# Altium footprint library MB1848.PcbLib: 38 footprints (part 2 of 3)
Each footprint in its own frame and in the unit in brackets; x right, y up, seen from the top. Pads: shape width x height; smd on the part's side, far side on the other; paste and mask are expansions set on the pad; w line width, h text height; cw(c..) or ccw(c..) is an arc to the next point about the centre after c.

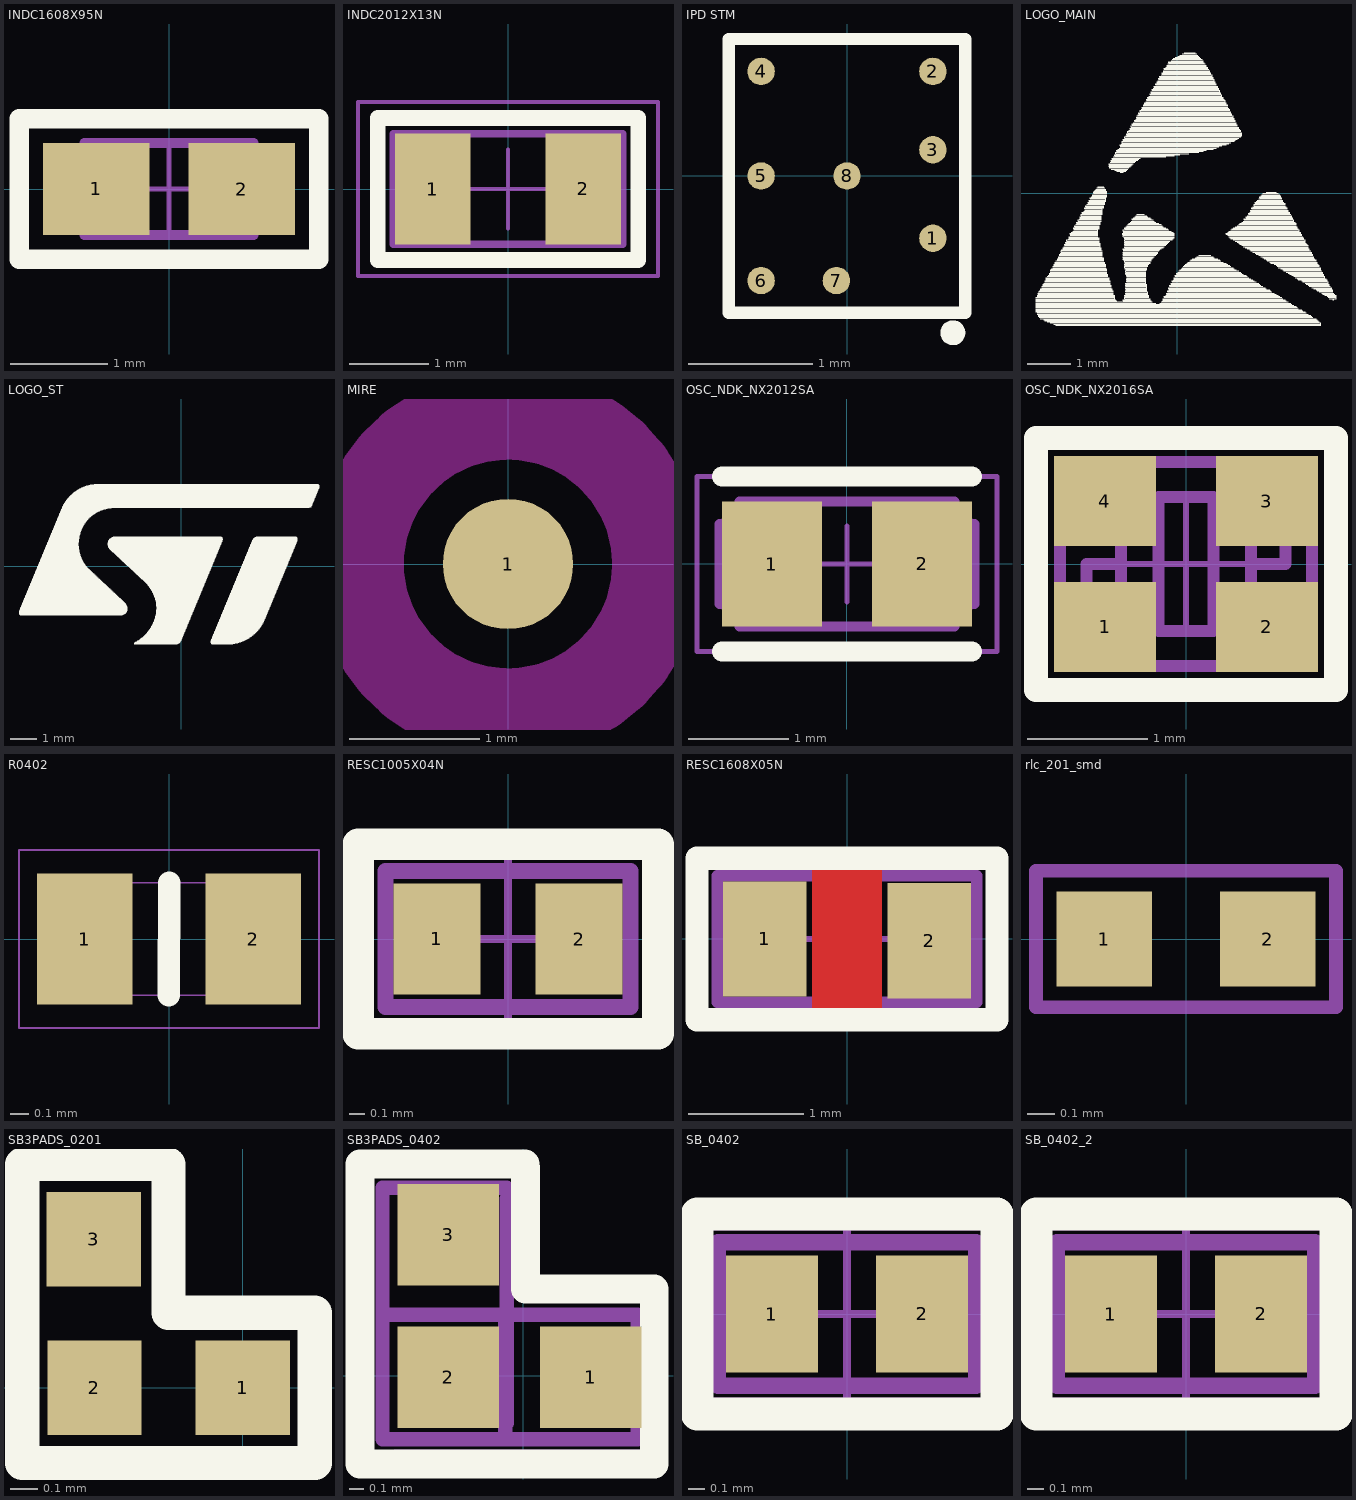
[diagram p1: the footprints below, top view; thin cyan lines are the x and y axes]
## INDC1608X95N [mm] "Chip Inductor, 2-Leads, Body 1.75x0.95x0.95mm (0603)"
height 0.95
pads (2):
  rect 1.1x0.95 smd: 1(-0.75,0) 2(0.75,0)
Top Overlay:
  lines w0.2: -1.548,-0.725 1.548,-0.725 1.548,0.725 -1.548,0.725 -1.548,-0.725
Top Assembly (Mech14):
  lines w0.1: -0.875,-0.475 0.875,-0.475 0.875,0.475 -0.875,0.475 -0.875,-0.475
  text ".Designator" at 0.473,0.376 h1.25
Mechanical 17:
  lines w0.05: -0.475,0 0.475,0 ; 0,-0.475 0,0.475 ; -1.55,-0.725 1.55,-0.725 1.55,0.725 -1.55,0.725 -1.55,-0.725
3D body "Chip Inductor 0603.step": height 0.8, standoff 0, extent -0.8,-0.475 0.8,0.475

## INDC2012X13N [mm] "Chip Inductor, 2-Leads, Body 2.0x1.2x1.3 (0805)"
height 1.3
pads (2):
  rect 0.96x1.4 smd: 1(-0.952,0) 2(0.952,0)
Top Overlay:
  lines w0.2: -1.65,-0.9 -1.65,0.9 1.65,0.9 1.65,-0.9 -1.65,-0.9
Top Assembly (Mech14):
  lines w0.1: -1.452,-0.7 1.452,-0.7 1.452,0.7 -1.452,0.7 -1.452,-0.7
  text ".Designator" at -0.677,0.372 h1.25
Mechanical 17:
  lines w0.05: -0.5,0 0.5,0 ; 0,-0.5 0,0.5 ; -1.9,-1.1 1.9,-1.1 1.9,1.1 -1.9,1.1 -1.9,-1.1
3D body "Chip InductorINDC2012X130N.step": height 1.18, standoff -0.02, extent -1,-0.65 1,0.65

## IPD STM [mm] "IPD STM STM32WL, Body 2.20 x 1.90 x 0.710 mm (LxWxH max)"
height 0.71
pads (8):
  round 0.22 smd mask+0.05: 1(0.69,-0.5) 2(0.69,0.84) 3(0.69,0.21) 4(-0.69,0.84) 5(-0.69,0) 6(-0.69,-0.84) 7(-0.085,-0.84) 8(0,0)
Top Overlay:
  circle w0.1: c0.85,-1.26 r0.05
  lines w0.1: -0.95,-1.1 -0.95,1.1 0.95,1.1 0.95,-1.1 -0.95,-1.1
Top Assembly (Mech14):
  lines w0.05: -0.95,-1.1 0.95,-1.1 0.95,1.1 -0.95,1.1 -0.95,-1.1
  text ".Designator" at -1.15,1.587 h1.25
3D body: height 0.71, standoff 0.05, extent -0.835,-1 0.835,1

## LOGO_MAIN [mm]
Top Overlay:
  drawing of 674 lines, arcs and shapes, not listed

## LOGO_ST [mm]
Top Overlay:
  drawing of 1036 lines, arcs and shapes, not listed

## MIRE [mm] "Fiducial Target Round , Pad 1.0mm, Keepout 3mm"
height 0.035
pads (1):
  round 1 smd mask+1: 1(0,0)
Top Layer keep-out:
  circle w0.7: c0,0 r1.15
3D body: height 0.04, standoff 0, extent -0.499,-0.499 0.499,0.499

## OSC_NDK_NX2012SA [mm] "Crystal, 2-Leads, Body 2.05x1.20x0.55mm (Tol:-/+0.05)"
height 0.55
pads (2):
  rect 1x1.25 smd: 1(-0.75,0) 2(0.75,0)
Top Overlay:
  lines w0.2: -1.25,-0.875 1.25,-0.875 ; -1.25,0.875 1.25,0.875
Top Assembly (Mech14):
  lines w0.1: -1.275,-0.4 cw(c-1.275,-0.6) -1.077,-0.625 1.077,-0.625 cw(c1.275,-0.6) 1.275,-0.4 1.275,0.4 cw(c1.275,0.6) 1.077,0.625 -1.077,0.625 cw(c-1.275,0.6) -1.275,0.4 -1.275,-0.4
  text ".Designator" at -0.65,-0.4 h1.25
Mechanical 17:
  lines w0.05: -0.381,0 0.381,0 ; 0,-0.381 0,0.381 ; -1.5,-0.875 1.5,-0.875 1.5,0.875 -1.5,0.875 -1.5,-0.875
3D body: height 0.55, standoff 0, extent -1.038,-0.625 1.025,0.625

## OSC_NDK_NX2016SA [mm] "Crystal, 4-Leads, Body 2.10x1.61x0.50mm (max), Pitch 1.35x1.05mm"
height 0.45
pads (4):
  rect 0.85x0.75 smd: 1(-0.675,-0.525) 2(0.675,-0.525) 3(0.675,0.525) 4(-0.675,0.525)
Top Overlay:
  lines w0.2: -1.25,-1.05 1.25,-1.05 1.25,1.05 -1.25,1.05 -1.25,-1.05
  text "." at -1.475,-1.675 h4
Top Assembly (Mech14):
  lines w0.1: -0.83,-0.45 -0.83,0 -0.54,0 ; -0.54,-0.3 -0.54,0.3 ; 0.54,-0.3 0.54,0.3 ; 0.54,0 0.83,0 0.83,0.45 ; -1.05,-0.65 cw(c-1.05,-0.85) -0.85,-0.85 0.85,-0.85 cw(c1.05,-0.85) 1.05,-0.65 1.05,0.65 cw(c1.05,0.85) 0.85,0.85 -0.85,0.85 cw(c-1.05,0.85) -1.05,0.65 -1.05,-0.65 ; -0.23,-0.56 -0.23,0.56 0.23,0.56 0.23,-0.56 -0.23,-0.56
  text "." at -0.7,-0.7 h3
  text ".Designator" at 0.54,-1.439 h1.25
Mechanical 17:
  lines w0.05: -0.5,0 0.5,0 ; 0,-0.5 0,0.5 ; -1.25,-1.05 1.25,-1.05 1.25,1.05 -1.25,1.05 -1.25,-1.05
3D body "OSC_NDK_NX2016SA.STEP": height 0.5, standoff 0, extent -1,-0.8 1,0.8

## R0402 [mm]
height 0.4
pads (2):
  rect 0.51x0.7 smd mask+0.05: 1(-0.45,0) 2(0.45,0)
Top Overlay:
  lines w0.12: 0,-0.3 0,0.3
Top Assembly (Mech14):
  lines w0.01: -0.45,-0.3 0.45,-0.3 0.45,0.3 -0.45,0.3 -0.45,-0.3
  text "'.Designator'" at -2,-0.5 h0.75
Mechanical 16:
  lines w0.01: -0.8,-0.475 -0.8,0.475 0.8,0.475 0.8,-0.475 -0.8,-0.475
3D body "R0402.STEP": height 0.34, standoff 0, extent -0.52,-0.3 0.52,0.3
3D body: height 0.4, standoff 0, extent -0.455,-0.305 0.455,0.305

## RESC1005X04N [mm] "Chip Resistor, 2-Leads, Body 1.00x0.50mm (0402)"
height 0.4
pads (2):
  rect 0.55x0.7 smd: 1(-0.45,0) 2(0.45,0)
Top Overlay:
  lines w0.2: -0.95,-0.6 -0.95,0.6 0.95,0.6 0.95,-0.6 -0.95,-0.6
Top Assembly (Mech14):
  lines w0.1: -0.775,-0.43 -0.775,0.43 0.775,0.43 0.775,-0.43 -0.775,-0.43
  text ".Designator" at 0.45,0.85 h1.25
Mechanical 17:
  lines w0.05: -0.5,0 0.5,0 ; 0,-0.5 0,0.5 ; -0.9,-0.525 -0.9,0.525 0.9,0.525 0.9,-0.525 -0.9,-0.525
3D body "RESC1005X04N.step": height 0.35, standoff 0, extent -0.5,-0.25 0.5,0.25

## RESC1608X05N [mm] "Chip Resistor, 2-Leads, Body 1.60x0.80mm (0603)"
height 0.5
pads (2):
  rect 0.725x1 smd: 1(-0.713,0) 2(0.712,-0.016)
Top Layer:
  pour cut-out: -0.3,0.7 0.3,0.7 0.3,-0.7 -0.3,-0.7
Top Overlay:
  lines w0.2: -1.3,-0.7 1.3,-0.7 1.3,0.7 -1.3,0.7 -1.3,-0.7
Top Assembly (Mech14):
  lines w0.1: -1.125,-0.55 -1.125,0.55 1.125,0.55 1.125,-0.55 -1.125,-0.55
  text ".Designator" at 0.65,0.4 h1.25
Mechanical 17:
  lines w0.05: -0.5,0 0.5,0 ; 0,-0.5 0,0.5 ; -1.3,-0.7 -1.3,0.7 1.3,0.7 1.3,-0.7 -1.3,-0.7
3D body "RESC1608X05N.step": height 0.45, standoff 0, extent -0.775,-0.425 0.775,0.425

## rlc_201_smd [mm]
pads (2):
  rect 0.35x0.35 smd paste+0 mask+0.025: 1(-0.3,0) 2(0.3,0)
Top Assembly (Mech14):
  lines w0.05: -0.55,-0.25 0.55,-0.25 0.55,0.25 -0.55,0.25 -0.55,-0.25
  text ".Designator" at -0.913,-1.119 h1.25
3D body: height 0.5, standoff 0.1, extent -0.3,-0.15 0.3,0.15

## SB3PADS_0201 [mm] "Solder Bridge 0 Ohm (0201)"
height 0.6
pads (3):
  rect 0.35x0.35 smd: 1(0,0) 2(-0.55,0) 3(-0.553,0.551)
Top Overlay:
  lines w0.127: -0.275,0.278 0.267,0.278 0.267,-0.273 ; -0.275,0.279 -0.275,0.83 -0.818,0.83 -0.818,-0.279 -0.13,-0.279 0.268,-0.279
Top Assembly (Mech14):
  lines w0.1: -0.813,-0.283 -0.813,0.825 -0.269,0.825 -0.269,0.276 0.271,0.276 0.271,-0.283 -0.813,-0.283
  text ".Designator" at -1.169,1.014 h1.25
3D body: height 0.25, standoff 0, extent -0.575,-0.15 0.025,0.15

## SB3PADS_0402 [mm] "Solder Bridge 0 Ohm (0402)"
height 0.6
pads (3):
  rect 0.7x0.7 smd: 1(0.466,-0.009) 2(-0.517,-0.009) 3(-0.517,0.974)
Top Overlay:
  lines w0.2: -1.127,1.461 -1.127,-0.609 0.905,-0.609 0.905,0.6 ; -1.127,1.464 0.012,1.464 ; 0.016,0.6 0.88,0.6 ; 0.016,0.611 0.016,1.441
Top Assembly (Mech14):
  lines w0.1: -0.972,1.291 -0.972,-0.439 0.791,-0.439 0.791,0.421 -0.948,0.421 ; -0.972,1.299 -0.113,1.299 ; -0.123,-0.439 -0.123,0.421 ; -0.113,-0.327 -0.113,1.223
  text ".Designator" at 0.009,3.108 h1.25
Mechanical 17:
  lines w0.05: -0.884,-0.534 0.916,-0.534
3D body: height 0.25, standoff 0, extent -0.792,-0.052 -0.292,0.948

## SB_0402 [mm] "Solder Bridge 0 Ohm (0402)"
height 0.6
pads (2):
  rect 0.55x0.7 smd: 1(-0.45,0) 2(0.45,0)
Top Overlay:
  lines w0.2: -0.9,-0.6 0.9,-0.6 0.9,0.6 -0.9,0.6 -0.9,-0.6
Top Assembly (Mech14):
  lines w0.1: -0.775,-0.43 0.775,-0.43 0.775,0.43 -0.775,0.43 -0.775,-0.43
  text ".Designator" at -1.1,0.4 h1.25
Mechanical 17:
  lines w0.05: -0.5,0 0.5,0 ; 0,-0.5 0,0.5 ; -0.9,-0.525 0.9,-0.525 0.9,0.525 -0.9,0.525 -0.9,-0.525
3D body: height 0.25, standoff 0, extent -0.5,-0.25 0.5,0.25

## SB_0402_2 [mm]
pads (2):
  rect 0.55x0.7 smd: 1(-0.45,0) 2(0.45,0)
Top Overlay:
  lines w0.2: -0.9,-0.6 0.9,-0.6 0.9,0.6 -0.9,0.6 -0.9,-0.6
Top Assembly (Mech14):
  lines w0.1: -0.775,-0.43 0.775,-0.43 0.775,0.43 -0.775,0.43 -0.775,-0.43
  text ".Designator" at -1.1,0.4 h1.25
Mechanical 17:
  lines w0.05: -0.5,0 0.5,0 ; 0,-0.5 0,0.5 ; -0.9,-0.525 0.9,-0.525 0.9,0.525 -0.9,0.525 -0.9,-0.525
3D body: height 0.25, standoff 0, extent -0.5,-0.25 0.5,0.25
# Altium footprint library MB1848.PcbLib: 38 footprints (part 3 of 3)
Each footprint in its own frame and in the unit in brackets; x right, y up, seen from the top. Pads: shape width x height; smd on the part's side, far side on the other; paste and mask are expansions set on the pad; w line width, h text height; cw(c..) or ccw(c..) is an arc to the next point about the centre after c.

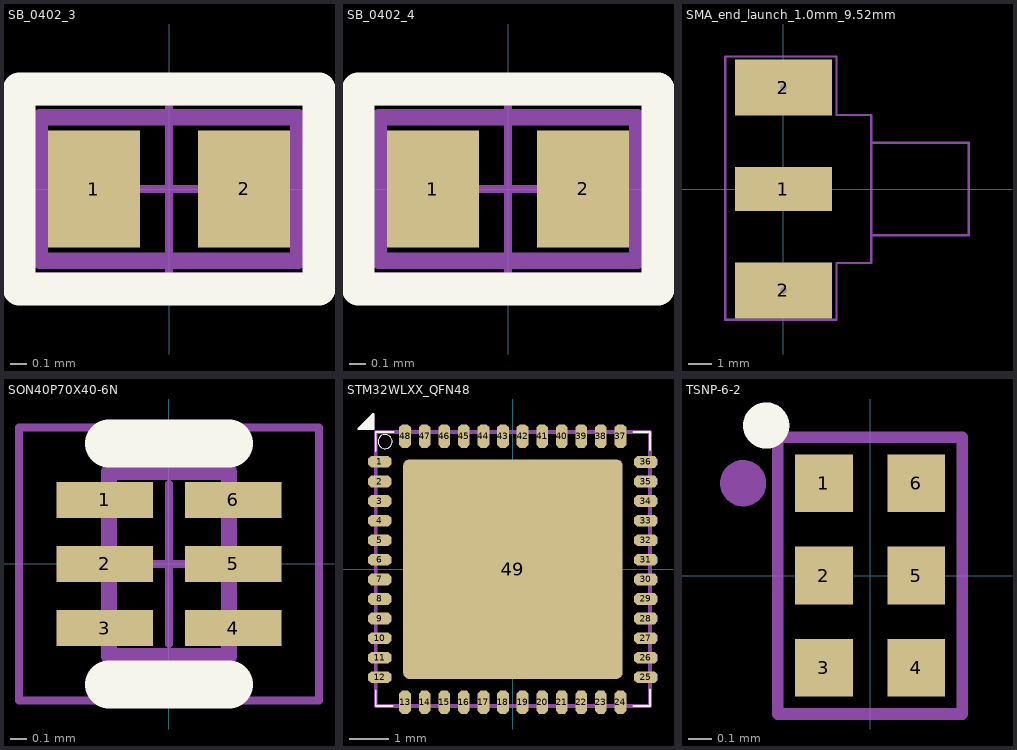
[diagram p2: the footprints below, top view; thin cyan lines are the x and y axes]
## SB_0402_3 [mm]
pads (2):
  rect 0.55x0.7 smd: 1(-0.45,0) 2(0.45,0)
Top Overlay:
  lines w0.2: -0.9,-0.6 0.9,-0.6 0.9,0.6 -0.9,0.6 -0.9,-0.6
Top Assembly (Mech14):
  lines w0.1: -0.775,-0.43 0.775,-0.43 0.775,0.43 -0.775,0.43 -0.775,-0.43
  text ".Designator" at -1.1,0.4 h1.25
Mechanical 17:
  lines w0.05: -0.5,0 0.5,0 ; 0,-0.5 0,0.5 ; -0.9,-0.525 0.9,-0.525 0.9,0.525 -0.9,0.525 -0.9,-0.525
3D body: height 0.25, standoff 0, extent -0.5,-0.25 0.5,0.25

## SB_0402_4 [mm]
pads (2):
  rect 0.55x0.7 smd: 1(-0.45,0) 2(0.45,0)
Top Overlay:
  lines w0.2: -0.9,-0.6 -0.9,0.6 0.9,0.6 0.9,-0.6 -0.9,-0.6
Top Assembly (Mech14):
  lines w0.1: -0.775,-0.43 -0.775,0.43 0.775,0.43 0.775,-0.43 -0.775,-0.43
  text ".Designator" at -1.1,0.4 h1.25
Mechanical 17:
  lines w0.05: -0.5,0 0.5,0 ; 0,-0.5 0,0.5 ; -0.9,-0.525 -0.9,0.525 0.9,0.525 0.9,-0.525 -0.9,-0.525
3D body: height 0.25, standoff 0, extent -0.5,-0.25 0.5,0.25

## SMA_end_launch_1.0mm_9.52mm [mm] "SMA end launch for 1.0mm PCB thickness; 9.52mm"
height 10
pads (3):
  rect 4.2x1.905 smd mask+0.05: 1(0,0)
  rect 4.2x2.413 hole 0.3 mask+0.05: 2(0,-4.38) 2(0,4.38)
Top Assembly (Mech14):
  lines w0.1: 3.796,-2 3.796,-3.2 2.295,-3.2 2.295,-5.65 -2.507,-5.65 -2.507,5.72 2.295,5.72 2.295,3.2 3.796,3.2 3.796,2 ; 3.796,-2 8,-2 8,2 3.796,2 ; 3.796,-2 3.796,2
3D body "142-0701-841.stp": height 3.96, standoff -3.96, extent -2.55,-4.739 11.725,4.786

## SON40P70X40-6N [mm] "SON, 6-Leads, Body 1.10x0.70mm, Pitch 0.40mm"
height 0.4
pads (6):
  rect 0.6x0.225 smd: 1(-0.4,0.4) 2(-0.4,0) 3(-0.4,-0.4) 4(0.4,-0.4) 5(0.4,0) 6(0.4,0.4)
Top Overlay:
  lines w0.3: -0.375,-0.75 0.375,-0.75 ; -0.375,0.75 0.375,0.75
  text "." at -1.2,0.9 h4
Top Assembly (Mech14):
  lines w0.1: -0.375,-0.575 0.375,-0.575 0.375,0.575 -0.375,0.575 -0.375,-0.575
  text ".Designator" at -0.629,0.683 h1.25
  text "." at -0.325,0.55 h4
Mechanical 17:
  lines w0.05: -0.5,0 0.5,0 ; 0,-0.5 0,0.5 ; -0.935,-0.85 0.935,-0.85 0.935,0.85 -0.935,0.85 -0.935,-0.85
3D body "SON40P70X40-6N.step": height 0.4, standoff 0, extent -0.376,-0.575 0.376,0.575

## STM32WLXX_QFN48 [mm] "QFN48 7x7x0.55mm pitch 0.5mm"
height 0.55
pads (49):
  oct 0.6x0.3 smd mask+0.06: 1(-3.398,2.746) 2(-3.398,2.239) 3(-3.398,1.739) 4(-3.398,1.239) 5(-3.398,0.739) 6(-3.398,0.239) 7(-3.398,-0.261) 8(-3.398,-0.761) 9(-3.398,-1.261) 10(-3.398,-1.761) 11(-3.398,-2.261) 12(-3.398,-2.761) 25(3.398,-2.761) 26(3.398,-2.261) 27(3.398,-1.761) 28(3.398,-1.261) 29(3.398,-0.761) 30(3.398,-0.261) 31(3.398,0.239) 32(3.398,0.739) 33(3.398,1.239) 34(3.398,1.739) 35(3.398,2.239) 36(3.398,2.739)
  oct 0.3x0.6 smd mask+0.06: 13(-2.752,-3.399) 14(-2.252,-3.399) 15(-1.752,-3.399) 16(-1.252,-3.399) 17(-0.752,-3.399) 18(-0.252,-3.399) 19(0.248,-3.399) 20(0.748,-3.399) 21(1.248,-3.399) 22(1.748,-3.399) 23(2.248,-3.399) 24(2.748,-3.399) 37(2.748,3.399) 38(2.248,3.399) 39(1.748,3.399) 40(1.248,3.399) 41(0.748,3.399) 42(0.248,3.399) 43(-0.252,3.399) 44(-0.752,3.399) 45(-1.252,3.399) 46(-1.752,3.399) 47(-2.252,3.399) 48(-2.752,3.399)
  rrect5% 5.6x5.6 smd paste-3 mask+0.08: 49(0,0)
Top Overlay:
  circle w0.025: c-3.263,3.258 r0.18
  lines w0.025: -3.502,-3.103 -3.502,-3.499 -3.079,-3.499 ; -3.502,3.489 -3.502,3.501 ; 3.077,3.501 3.498,3.501 ; 3.498,-3.499 3.498,-3.067
  lines w0.05: -3.869,3.634 -3.565,3.634 ; -3.869,3.659 -3.565,3.659 ; -3.793,3.583 -3.607,3.785 ; -3.59,3.608 -3.895,3.608 ; -3.59,3.684 -3.692,3.684 -3.615,3.659 -3.59,3.735 -3.895,3.583 -3.59,3.583 -3.59,3.924 -3.844,3.634 -3.565,3.888 -3.819,3.608 -3.895,3.608 ; -3.502,-3.103 -3.502,-3.499 -3.079,-3.499 ; -3.502,3.019 -3.502,3.489 ; -3.502,3.501 -3.044,3.501 ; 3.077,-3.499 3.498,-3.499 3.498,-3.067 ; 3.077,3.501 3.498,3.501 3.498,3.044 ; -3.895,3.608 -3.565,3.964 ; -3.565,3.964 -3.946,3.583 -3.565,3.583 -3.565,3.964
Top Paste:
  rectangle: 1.091,1.064 2.541,2.514
  rectangle: -0.713,1.064 0.737,2.514
  rectangle: -2.493,1.064 -1.043,2.514
  rectangle: 1.092,-0.71 2.542,0.74
  rectangle: -0.712,-0.71 0.738,0.74
  rectangle: -2.492,-0.71 -1.042,0.74
  rectangle: -2.492,-2.488 -1.042,-1.038
  rectangle: -0.712,-2.488 0.738,-1.038
  rectangle: 1.092,-2.488 2.542,-1.038
Top Assembly (Mech14):
  circle w0.025: c-3.263,3.258 r0.18
  lines w0.05: -3.869,3.634 -3.565,3.634 ; -3.869,3.659 -3.565,3.659 ; -3.793,3.583 -3.607,3.785 ; -3.59,3.608 -3.895,3.608 ; -3.59,3.684 -3.692,3.684 -3.615,3.659 -3.59,3.735 -3.895,3.583 -3.59,3.583 -3.59,3.924 -3.844,3.634 -3.565,3.888 -3.819,3.608 -3.895,3.608 ; -3.895,3.608 -3.565,3.964 ; -3.565,3.964 -3.565,3.583 -3.946,3.583 -3.565,3.964
  lines w0.1: -3.502,-3.499 -3.079,-3.499 ; -3.502,-3.499 -3.079,-3.499 ; -3.502,-3.499 -3.502,-3.103 ; -3.502,-3.499 -3.502,-3.103 ; -3.502,-3.103 -3.502,3.489 -3.502,3.501 3.077,3.501 ; -3.079,-3.499 3.498,-3.499 ; 3.077,3.501 3.498,3.501 ; 3.077,3.501 3.498,3.501 ; 3.498,-3.499 3.498,-3.067 ; 3.498,-3.499 3.498,-3.067 ; 3.498,-3.067 3.498,3.501
  text ".Designator" at -3.004,3.971 h1.25
3D body "User Library-QFN48_7x7.step": height 0.78, standoff -0.02, extent -3.511,-3.509 3.509,3.511

## TSNP-6-2 [mm] "TSNP-6-2; Body 1.1 x 0.7 mm (LxW typ)"
height 0.45
pads (6):
  rect 0.25x0.25 smd paste-0.025 mask+0.025: 1(-0.2,0.4) 2(-0.2,0) 3(-0.2,-0.4) 4(0.2,-0.4) 5(0.2,0) 6(0.2,0.4)
Top Overlay:
  circle w0.1: c-0.45,0.65 r0.05
Top Assembly (Mech14):
  circle w0.1: c-0.55,0.4 r0.05
  lines w0.05: -0.4,-0.6 -0.4,0.6 0.4,0.6 0.4,-0.6 -0.4,-0.6
  text ".Designator" at -0.727,0.874 h1.25
3D body: height 0.45, standoff 0.05, extent -0.35,-0.55 0.35,0.55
